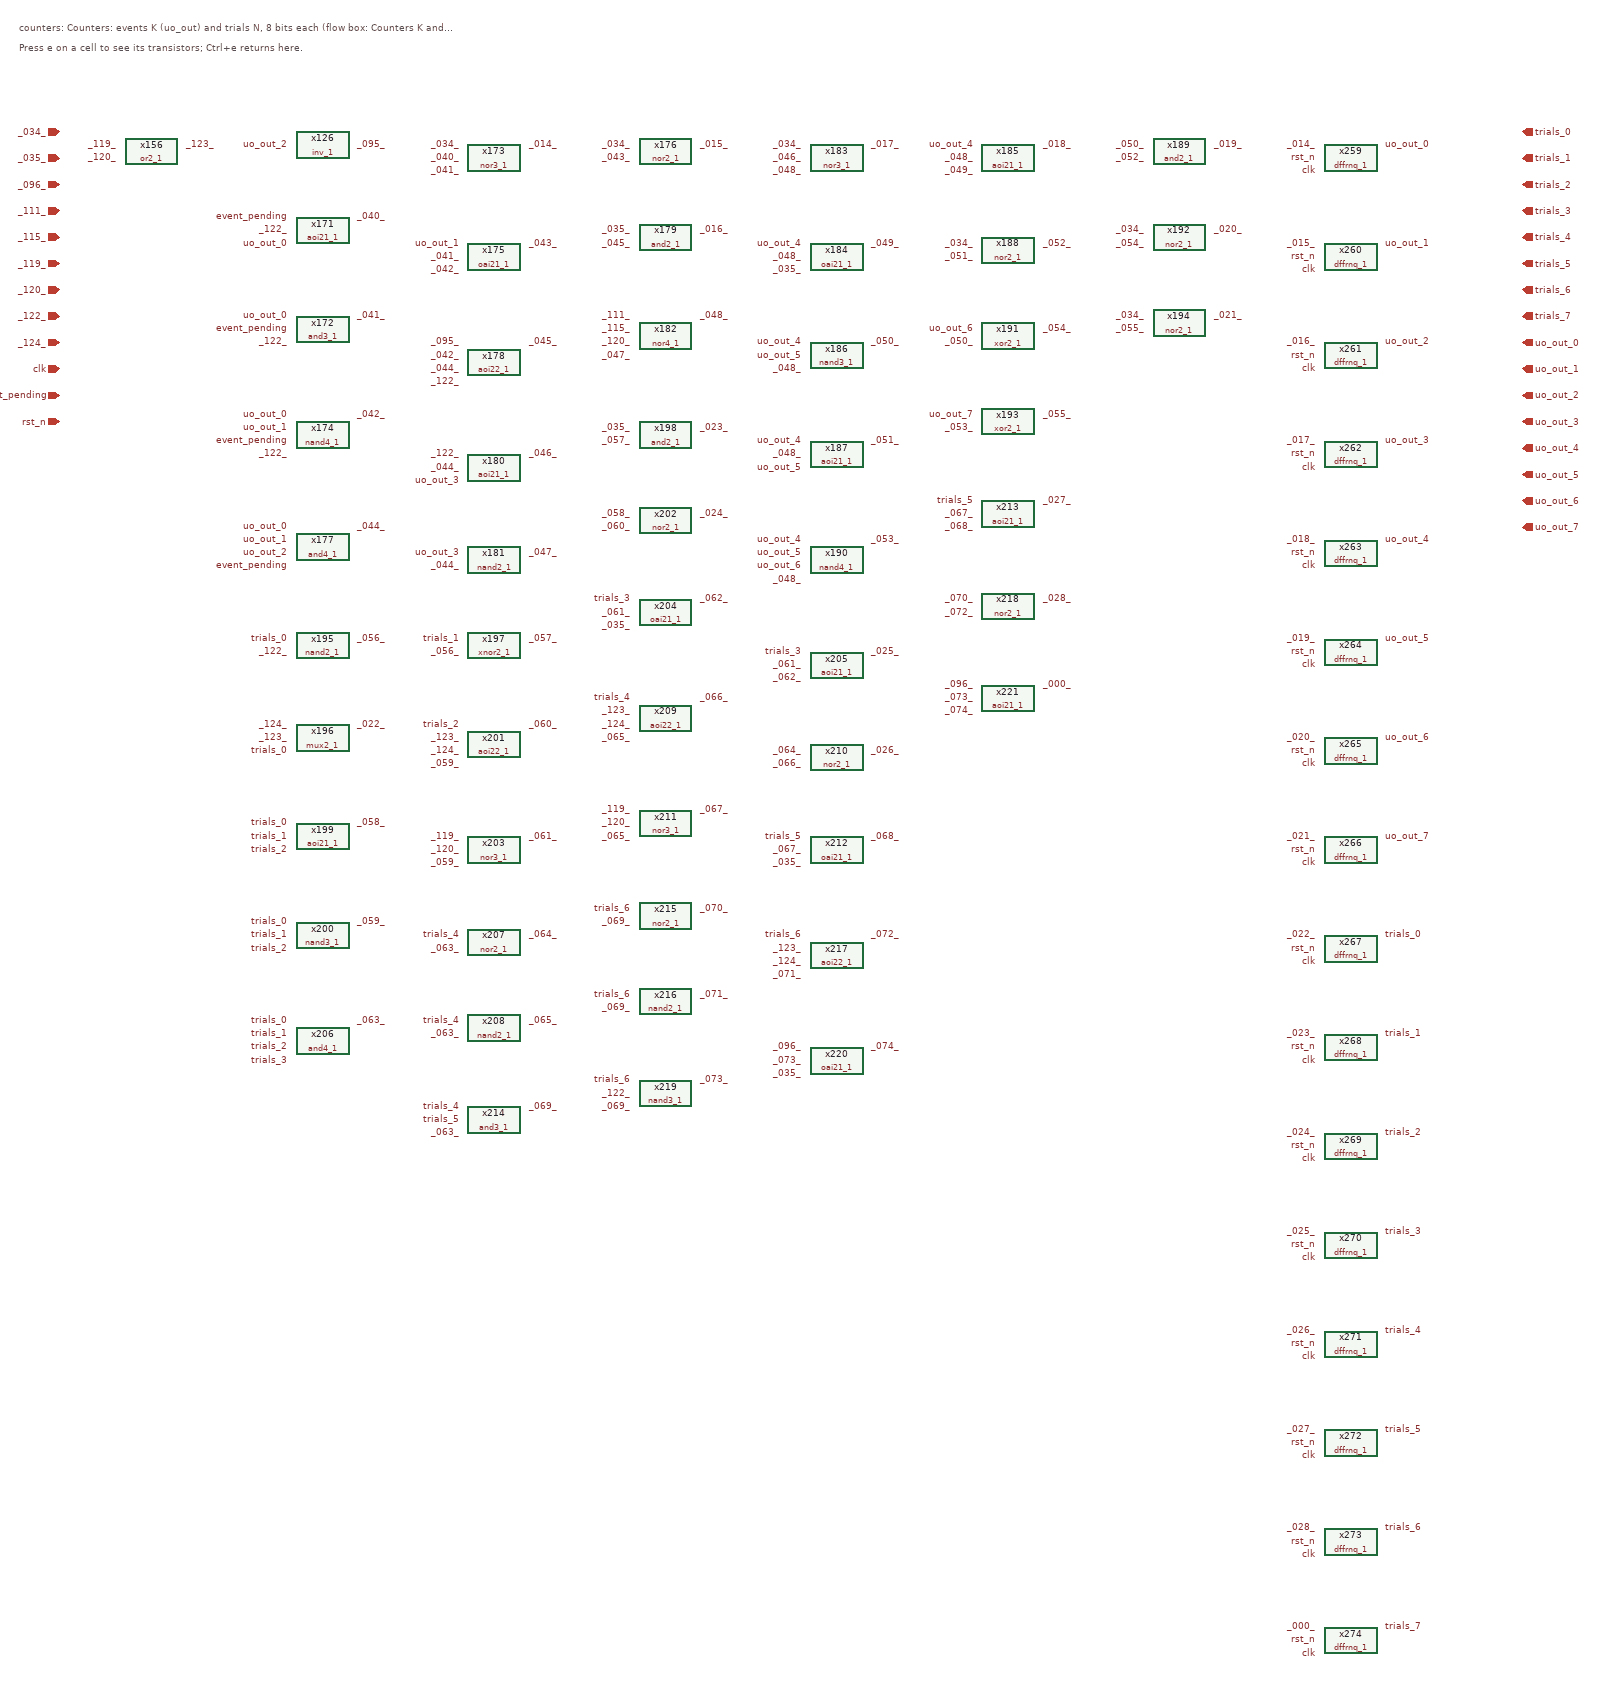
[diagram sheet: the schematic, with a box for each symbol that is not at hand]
v {xschem version=3.4.4 file_version=1.2}
G {}
K {}
V {}
S {}
E {}
T {counters: Counters: events K (uo_out) and trials N, 8 bits each   (flow box: Counters K and N)} 0 -170 0 0 0.4 0.4 {}
T {Press e on a cell to see its transistors; Ctrl+e returns here.} 0 -140 0 0 0.25 0.25 {}
C {@@ROOT@@/cells_tx/inv_1.sym} 460 20 0 0 {name=x126}
C {devices/lab_pin.sym} 410 20 0 0 {name=l1 lab=uo_out_2}
C {devices/lab_pin.sym} 510 20 0 1 {name=l2 lab=_095_}
C {@@ROOT@@/cells_tx/or2_1.sym} 200 30 0 0 {name=x156}
C {devices/lab_pin.sym} 150 20 0 0 {name=l3 lab=_119_}
C {devices/lab_pin.sym} 150 40 0 0 {name=l4 lab=_120_}
C {devices/lab_pin.sym} 250 20 0 1 {name=l5 lab=_123_}
C {@@ROOT@@/cells_tx/aoi21_1.sym} 460 150 0 0 {name=x171}
C {devices/lab_pin.sym} 410 130 0 0 {name=l6 lab=event_pending}
C {devices/lab_pin.sym} 410 150 0 0 {name=l7 lab=_122_}
C {devices/lab_pin.sym} 410 170 0 0 {name=l8 lab=uo_out_0}
C {devices/lab_pin.sym} 510 130 0 1 {name=l9 lab=_040_}
C {@@ROOT@@/cells_tx/and3_1.sym} 460 300 0 0 {name=x172}
C {devices/lab_pin.sym} 410 280 0 0 {name=l10 lab=uo_out_0}
C {devices/lab_pin.sym} 410 300 0 0 {name=l11 lab=event_pending}
C {devices/lab_pin.sym} 410 320 0 0 {name=l12 lab=_122_}
C {devices/lab_pin.sym} 510 280 0 1 {name=l13 lab=_041_}
C {@@ROOT@@/cells_tx/nor3_1.sym} 720 40 0 0 {name=x173}
C {devices/lab_pin.sym} 670 20 0 0 {name=l14 lab=_034_}
C {devices/lab_pin.sym} 670 40 0 0 {name=l15 lab=_040_}
C {devices/lab_pin.sym} 670 60 0 0 {name=l16 lab=_041_}
C {devices/lab_pin.sym} 770 20 0 1 {name=l17 lab=_014_}
C {@@ROOT@@/cells_tx/nand4_1.sym} 460 460 0 0 {name=x174}
C {devices/lab_pin.sym} 410 430 0 0 {name=l18 lab=uo_out_0}
C {devices/lab_pin.sym} 410 450 0 0 {name=l19 lab=uo_out_1}
C {devices/lab_pin.sym} 410 470 0 0 {name=l20 lab=event_pending}
C {devices/lab_pin.sym} 410 490 0 0 {name=l21 lab=_122_}
C {devices/lab_pin.sym} 510 430 0 1 {name=l22 lab=_042_}
C {@@ROOT@@/cells_tx/oai21_1.sym} 720 190 0 0 {name=x175}
C {devices/lab_pin.sym} 670 170 0 0 {name=l23 lab=uo_out_1}
C {devices/lab_pin.sym} 670 190 0 0 {name=l24 lab=_041_}
C {devices/lab_pin.sym} 670 210 0 0 {name=l25 lab=_042_}
C {devices/lab_pin.sym} 770 170 0 1 {name=l26 lab=_043_}
C {@@ROOT@@/cells_tx/nor2_1.sym} 980 30 0 0 {name=x176}
C {devices/lab_pin.sym} 930 20 0 0 {name=l27 lab=_034_}
C {devices/lab_pin.sym} 930 40 0 0 {name=l28 lab=_043_}
C {devices/lab_pin.sym} 1030 20 0 1 {name=l29 lab=_015_}
C {@@ROOT@@/cells_tx/and4_1.sym} 460 630 0 0 {name=x177}
C {devices/lab_pin.sym} 410 600 0 0 {name=l30 lab=uo_out_0}
C {devices/lab_pin.sym} 410 620 0 0 {name=l31 lab=uo_out_1}
C {devices/lab_pin.sym} 410 640 0 0 {name=l32 lab=uo_out_2}
C {devices/lab_pin.sym} 410 660 0 0 {name=l33 lab=event_pending}
C {devices/lab_pin.sym} 510 600 0 1 {name=l34 lab=_044_}
C {@@ROOT@@/cells_tx/aoi22_1.sym} 720 350 0 0 {name=x178}
C {devices/lab_pin.sym} 670 320 0 0 {name=l35 lab=_095_}
C {devices/lab_pin.sym} 670 340 0 0 {name=l36 lab=_042_}
C {devices/lab_pin.sym} 670 360 0 0 {name=l37 lab=_044_}
C {devices/lab_pin.sym} 670 380 0 0 {name=l38 lab=_122_}
C {devices/lab_pin.sym} 770 320 0 1 {name=l39 lab=_045_}
C {@@ROOT@@/cells_tx/and2_1.sym} 980 160 0 0 {name=x179}
C {devices/lab_pin.sym} 930 150 0 0 {name=l40 lab=_035_}
C {devices/lab_pin.sym} 930 170 0 0 {name=l41 lab=_045_}
C {devices/lab_pin.sym} 1030 150 0 1 {name=l42 lab=_016_}
C {@@ROOT@@/cells_tx/aoi21_1.sym} 720 510 0 0 {name=x180}
C {devices/lab_pin.sym} 670 490 0 0 {name=l43 lab=_122_}
C {devices/lab_pin.sym} 670 510 0 0 {name=l44 lab=_044_}
C {devices/lab_pin.sym} 670 530 0 0 {name=l45 lab=uo_out_3}
C {devices/lab_pin.sym} 770 490 0 1 {name=l46 lab=_046_}
C {@@ROOT@@/cells_tx/nand2_1.sym} 720 650 0 0 {name=x181}
C {devices/lab_pin.sym} 670 640 0 0 {name=l47 lab=uo_out_3}
C {devices/lab_pin.sym} 670 660 0 0 {name=l48 lab=_044_}
C {devices/lab_pin.sym} 770 640 0 1 {name=l49 lab=_047_}
C {@@ROOT@@/cells_tx/nor4_1.sym} 980 310 0 0 {name=x182}
C {devices/lab_pin.sym} 930 280 0 0 {name=l50 lab=_111_}
C {devices/lab_pin.sym} 930 300 0 0 {name=l51 lab=_115_}
C {devices/lab_pin.sym} 930 320 0 0 {name=l52 lab=_120_}
C {devices/lab_pin.sym} 930 340 0 0 {name=l53 lab=_047_}
C {devices/lab_pin.sym} 1030 280 0 1 {name=l54 lab=_048_}
C {@@ROOT@@/cells_tx/nor3_1.sym} 1240 40 0 0 {name=x183}
C {devices/lab_pin.sym} 1190 20 0 0 {name=l55 lab=_034_}
C {devices/lab_pin.sym} 1190 40 0 0 {name=l56 lab=_046_}
C {devices/lab_pin.sym} 1190 60 0 0 {name=l57 lab=_048_}
C {devices/lab_pin.sym} 1290 20 0 1 {name=l58 lab=_017_}
C {@@ROOT@@/cells_tx/oai21_1.sym} 1240 190 0 0 {name=x184}
C {devices/lab_pin.sym} 1190 170 0 0 {name=l59 lab=uo_out_4}
C {devices/lab_pin.sym} 1190 190 0 0 {name=l60 lab=_048_}
C {devices/lab_pin.sym} 1190 210 0 0 {name=l61 lab=_035_}
C {devices/lab_pin.sym} 1290 170 0 1 {name=l62 lab=_049_}
C {@@ROOT@@/cells_tx/aoi21_1.sym} 1500 40 0 0 {name=x185}
C {devices/lab_pin.sym} 1450 20 0 0 {name=l63 lab=uo_out_4}
C {devices/lab_pin.sym} 1450 40 0 0 {name=l64 lab=_048_}
C {devices/lab_pin.sym} 1450 60 0 0 {name=l65 lab=_049_}
C {devices/lab_pin.sym} 1550 20 0 1 {name=l66 lab=_018_}
C {@@ROOT@@/cells_tx/nand3_1.sym} 1240 340 0 0 {name=x186}
C {devices/lab_pin.sym} 1190 320 0 0 {name=l67 lab=uo_out_4}
C {devices/lab_pin.sym} 1190 340 0 0 {name=l68 lab=uo_out_5}
C {devices/lab_pin.sym} 1190 360 0 0 {name=l69 lab=_048_}
C {devices/lab_pin.sym} 1290 320 0 1 {name=l70 lab=_050_}
C {@@ROOT@@/cells_tx/aoi21_1.sym} 1240 490 0 0 {name=x187}
C {devices/lab_pin.sym} 1190 470 0 0 {name=l71 lab=uo_out_4}
C {devices/lab_pin.sym} 1190 490 0 0 {name=l72 lab=_048_}
C {devices/lab_pin.sym} 1190 510 0 0 {name=l73 lab=uo_out_5}
C {devices/lab_pin.sym} 1290 470 0 1 {name=l74 lab=_051_}
C {@@ROOT@@/cells_tx/nor2_1.sym} 1500 180 0 0 {name=x188}
C {devices/lab_pin.sym} 1450 170 0 0 {name=l75 lab=_034_}
C {devices/lab_pin.sym} 1450 190 0 0 {name=l76 lab=_051_}
C {devices/lab_pin.sym} 1550 170 0 1 {name=l77 lab=_052_}
C {@@ROOT@@/cells_tx/and2_1.sym} 1760 30 0 0 {name=x189}
C {devices/lab_pin.sym} 1710 20 0 0 {name=l78 lab=_050_}
C {devices/lab_pin.sym} 1710 40 0 0 {name=l79 lab=_052_}
C {devices/lab_pin.sym} 1810 20 0 1 {name=l80 lab=_019_}
C {@@ROOT@@/cells_tx/nand4_1.sym} 1240 650 0 0 {name=x190}
C {devices/lab_pin.sym} 1190 620 0 0 {name=l81 lab=uo_out_4}
C {devices/lab_pin.sym} 1190 640 0 0 {name=l82 lab=uo_out_5}
C {devices/lab_pin.sym} 1190 660 0 0 {name=l83 lab=uo_out_6}
C {devices/lab_pin.sym} 1190 680 0 0 {name=l84 lab=_048_}
C {devices/lab_pin.sym} 1290 620 0 1 {name=l85 lab=_053_}
C {@@ROOT@@/cells_tx/xor2_1.sym} 1500 310 0 0 {name=x191}
C {devices/lab_pin.sym} 1450 300 0 0 {name=l86 lab=uo_out_6}
C {devices/lab_pin.sym} 1450 320 0 0 {name=l87 lab=_050_}
C {devices/lab_pin.sym} 1550 300 0 1 {name=l88 lab=_054_}
C {@@ROOT@@/cells_tx/nor2_1.sym} 1760 160 0 0 {name=x192}
C {devices/lab_pin.sym} 1710 150 0 0 {name=l89 lab=_034_}
C {devices/lab_pin.sym} 1710 170 0 0 {name=l90 lab=_054_}
C {devices/lab_pin.sym} 1810 150 0 1 {name=l91 lab=_020_}
C {@@ROOT@@/cells_tx/xor2_1.sym} 1500 440 0 0 {name=x193}
C {devices/lab_pin.sym} 1450 430 0 0 {name=l92 lab=uo_out_7}
C {devices/lab_pin.sym} 1450 450 0 0 {name=l93 lab=_053_}
C {devices/lab_pin.sym} 1550 430 0 1 {name=l94 lab=_055_}
C {@@ROOT@@/cells_tx/nor2_1.sym} 1760 290 0 0 {name=x194}
C {devices/lab_pin.sym} 1710 280 0 0 {name=l95 lab=_034_}
C {devices/lab_pin.sym} 1710 300 0 0 {name=l96 lab=_055_}
C {devices/lab_pin.sym} 1810 280 0 1 {name=l97 lab=_021_}
C {@@ROOT@@/cells_tx/nand2_1.sym} 460 780 0 0 {name=x195}
C {devices/lab_pin.sym} 410 770 0 0 {name=l98 lab=trials_0}
C {devices/lab_pin.sym} 410 790 0 0 {name=l99 lab=_122_}
C {devices/lab_pin.sym} 510 770 0 1 {name=l100 lab=_056_}
C {@@ROOT@@/cells_tx/mux2_1.sym} 460 920 0 0 {name=x196}
C {devices/lab_pin.sym} 410 900 0 0 {name=l101 lab=_124_}
C {devices/lab_pin.sym} 410 920 0 0 {name=l102 lab=_123_}
C {devices/lab_pin.sym} 410 940 0 0 {name=l103 lab=trials_0}
C {devices/lab_pin.sym} 510 900 0 1 {name=l104 lab=_022_}
C {@@ROOT@@/cells_tx/xnor2_1.sym} 720 780 0 0 {name=x197}
C {devices/lab_pin.sym} 670 770 0 0 {name=l105 lab=trials_1}
C {devices/lab_pin.sym} 670 790 0 0 {name=l106 lab=_056_}
C {devices/lab_pin.sym} 770 770 0 1 {name=l107 lab=_057_}
C {@@ROOT@@/cells_tx/and2_1.sym} 980 460 0 0 {name=x198}
C {devices/lab_pin.sym} 930 450 0 0 {name=l108 lab=_035_}
C {devices/lab_pin.sym} 930 470 0 0 {name=l109 lab=_057_}
C {devices/lab_pin.sym} 1030 450 0 1 {name=l110 lab=_023_}
C {@@ROOT@@/cells_tx/aoi21_1.sym} 460 1070 0 0 {name=x199}
C {devices/lab_pin.sym} 410 1050 0 0 {name=l111 lab=trials_0}
C {devices/lab_pin.sym} 410 1070 0 0 {name=l112 lab=trials_1}
C {devices/lab_pin.sym} 410 1090 0 0 {name=l113 lab=trials_2}
C {devices/lab_pin.sym} 510 1050 0 1 {name=l114 lab=_058_}
C {@@ROOT@@/cells_tx/nand3_1.sym} 460 1220 0 0 {name=x200}
C {devices/lab_pin.sym} 410 1200 0 0 {name=l115 lab=trials_0}
C {devices/lab_pin.sym} 410 1220 0 0 {name=l116 lab=trials_1}
C {devices/lab_pin.sym} 410 1240 0 0 {name=l117 lab=trials_2}
C {devices/lab_pin.sym} 510 1200 0 1 {name=l118 lab=_059_}
C {@@ROOT@@/cells_tx/aoi22_1.sym} 720 930 0 0 {name=x201}
C {devices/lab_pin.sym} 670 900 0 0 {name=l119 lab=trials_2}
C {devices/lab_pin.sym} 670 920 0 0 {name=l120 lab=_123_}
C {devices/lab_pin.sym} 670 940 0 0 {name=l121 lab=_124_}
C {devices/lab_pin.sym} 670 960 0 0 {name=l122 lab=_059_}
C {devices/lab_pin.sym} 770 900 0 1 {name=l123 lab=_060_}
C {@@ROOT@@/cells_tx/nor2_1.sym} 980 590 0 0 {name=x202}
C {devices/lab_pin.sym} 930 580 0 0 {name=l124 lab=_058_}
C {devices/lab_pin.sym} 930 600 0 0 {name=l125 lab=_060_}
C {devices/lab_pin.sym} 1030 580 0 1 {name=l126 lab=_024_}
C {@@ROOT@@/cells_tx/nor3_1.sym} 720 1090 0 0 {name=x203}
C {devices/lab_pin.sym} 670 1070 0 0 {name=l127 lab=_119_}
C {devices/lab_pin.sym} 670 1090 0 0 {name=l128 lab=_120_}
C {devices/lab_pin.sym} 670 1110 0 0 {name=l129 lab=_059_}
C {devices/lab_pin.sym} 770 1070 0 1 {name=l130 lab=_061_}
C {@@ROOT@@/cells_tx/oai21_1.sym} 980 730 0 0 {name=x204}
C {devices/lab_pin.sym} 930 710 0 0 {name=l131 lab=trials_3}
C {devices/lab_pin.sym} 930 730 0 0 {name=l132 lab=_061_}
C {devices/lab_pin.sym} 930 750 0 0 {name=l133 lab=_035_}
C {devices/lab_pin.sym} 1030 710 0 1 {name=l134 lab=_062_}
C {@@ROOT@@/cells_tx/aoi21_1.sym} 1240 810 0 0 {name=x205}
C {devices/lab_pin.sym} 1190 790 0 0 {name=l135 lab=trials_3}
C {devices/lab_pin.sym} 1190 810 0 0 {name=l136 lab=_061_}
C {devices/lab_pin.sym} 1190 830 0 0 {name=l137 lab=_062_}
C {devices/lab_pin.sym} 1290 790 0 1 {name=l138 lab=_025_}
C {@@ROOT@@/cells_tx/and4_1.sym} 460 1380 0 0 {name=x206}
C {devices/lab_pin.sym} 410 1350 0 0 {name=l139 lab=trials_0}
C {devices/lab_pin.sym} 410 1370 0 0 {name=l140 lab=trials_1}
C {devices/lab_pin.sym} 410 1390 0 0 {name=l141 lab=trials_2}
C {devices/lab_pin.sym} 410 1410 0 0 {name=l142 lab=trials_3}
C {devices/lab_pin.sym} 510 1350 0 1 {name=l143 lab=_063_}
C {@@ROOT@@/cells_tx/nor2_1.sym} 720 1230 0 0 {name=x207}
C {devices/lab_pin.sym} 670 1220 0 0 {name=l144 lab=trials_4}
C {devices/lab_pin.sym} 670 1240 0 0 {name=l145 lab=_063_}
C {devices/lab_pin.sym} 770 1220 0 1 {name=l146 lab=_064_}
C {@@ROOT@@/cells_tx/nand2_1.sym} 720 1360 0 0 {name=x208}
C {devices/lab_pin.sym} 670 1350 0 0 {name=l147 lab=trials_4}
C {devices/lab_pin.sym} 670 1370 0 0 {name=l148 lab=_063_}
C {devices/lab_pin.sym} 770 1350 0 1 {name=l149 lab=_065_}
C {@@ROOT@@/cells_tx/aoi22_1.sym} 980 890 0 0 {name=x209}
C {devices/lab_pin.sym} 930 860 0 0 {name=l150 lab=trials_4}
C {devices/lab_pin.sym} 930 880 0 0 {name=l151 lab=_123_}
C {devices/lab_pin.sym} 930 900 0 0 {name=l152 lab=_124_}
C {devices/lab_pin.sym} 930 920 0 0 {name=l153 lab=_065_}
C {devices/lab_pin.sym} 1030 860 0 1 {name=l154 lab=_066_}
C {@@ROOT@@/cells_tx/nor2_1.sym} 1240 950 0 0 {name=x210}
C {devices/lab_pin.sym} 1190 940 0 0 {name=l155 lab=_064_}
C {devices/lab_pin.sym} 1190 960 0 0 {name=l156 lab=_066_}
C {devices/lab_pin.sym} 1290 940 0 1 {name=l157 lab=_026_}
C {@@ROOT@@/cells_tx/nor3_1.sym} 980 1050 0 0 {name=x211}
C {devices/lab_pin.sym} 930 1030 0 0 {name=l158 lab=_119_}
C {devices/lab_pin.sym} 930 1050 0 0 {name=l159 lab=_120_}
C {devices/lab_pin.sym} 930 1070 0 0 {name=l160 lab=_065_}
C {devices/lab_pin.sym} 1030 1030 0 1 {name=l161 lab=_067_}
C {@@ROOT@@/cells_tx/oai21_1.sym} 1240 1090 0 0 {name=x212}
C {devices/lab_pin.sym} 1190 1070 0 0 {name=l162 lab=trials_5}
C {devices/lab_pin.sym} 1190 1090 0 0 {name=l163 lab=_067_}
C {devices/lab_pin.sym} 1190 1110 0 0 {name=l164 lab=_035_}
C {devices/lab_pin.sym} 1290 1070 0 1 {name=l165 lab=_068_}
C {@@ROOT@@/cells_tx/aoi21_1.sym} 1500 580 0 0 {name=x213}
C {devices/lab_pin.sym} 1450 560 0 0 {name=l166 lab=trials_5}
C {devices/lab_pin.sym} 1450 580 0 0 {name=l167 lab=_067_}
C {devices/lab_pin.sym} 1450 600 0 0 {name=l168 lab=_068_}
C {devices/lab_pin.sym} 1550 560 0 1 {name=l169 lab=_027_}
C {@@ROOT@@/cells_tx/and3_1.sym} 720 1500 0 0 {name=x214}
C {devices/lab_pin.sym} 670 1480 0 0 {name=l170 lab=trials_4}
C {devices/lab_pin.sym} 670 1500 0 0 {name=l171 lab=trials_5}
C {devices/lab_pin.sym} 670 1520 0 0 {name=l172 lab=_063_}
C {devices/lab_pin.sym} 770 1480 0 1 {name=l173 lab=_069_}
C {@@ROOT@@/cells_tx/nor2_1.sym} 980 1190 0 0 {name=x215}
C {devices/lab_pin.sym} 930 1180 0 0 {name=l174 lab=trials_6}
C {devices/lab_pin.sym} 930 1200 0 0 {name=l175 lab=_069_}
C {devices/lab_pin.sym} 1030 1180 0 1 {name=l176 lab=_070_}
C {@@ROOT@@/cells_tx/nand2_1.sym} 980 1320 0 0 {name=x216}
C {devices/lab_pin.sym} 930 1310 0 0 {name=l177 lab=trials_6}
C {devices/lab_pin.sym} 930 1330 0 0 {name=l178 lab=_069_}
C {devices/lab_pin.sym} 1030 1310 0 1 {name=l179 lab=_071_}
C {@@ROOT@@/cells_tx/aoi22_1.sym} 1240 1250 0 0 {name=x217}
C {devices/lab_pin.sym} 1190 1220 0 0 {name=l180 lab=trials_6}
C {devices/lab_pin.sym} 1190 1240 0 0 {name=l181 lab=_123_}
C {devices/lab_pin.sym} 1190 1260 0 0 {name=l182 lab=_124_}
C {devices/lab_pin.sym} 1190 1280 0 0 {name=l183 lab=_071_}
C {devices/lab_pin.sym} 1290 1220 0 1 {name=l184 lab=_072_}
C {@@ROOT@@/cells_tx/nor2_1.sym} 1500 720 0 0 {name=x218}
C {devices/lab_pin.sym} 1450 710 0 0 {name=l185 lab=_070_}
C {devices/lab_pin.sym} 1450 730 0 0 {name=l186 lab=_072_}
C {devices/lab_pin.sym} 1550 710 0 1 {name=l187 lab=_028_}
C {@@ROOT@@/cells_tx/nand3_1.sym} 980 1460 0 0 {name=x219}
C {devices/lab_pin.sym} 930 1440 0 0 {name=l188 lab=trials_6}
C {devices/lab_pin.sym} 930 1460 0 0 {name=l189 lab=_122_}
C {devices/lab_pin.sym} 930 1480 0 0 {name=l190 lab=_069_}
C {devices/lab_pin.sym} 1030 1440 0 1 {name=l191 lab=_073_}
C {@@ROOT@@/cells_tx/oai21_1.sym} 1240 1410 0 0 {name=x220}
C {devices/lab_pin.sym} 1190 1390 0 0 {name=l192 lab=_096_}
C {devices/lab_pin.sym} 1190 1410 0 0 {name=l193 lab=_073_}
C {devices/lab_pin.sym} 1190 1430 0 0 {name=l194 lab=_035_}
C {devices/lab_pin.sym} 1290 1390 0 1 {name=l195 lab=_074_}
C {@@ROOT@@/cells_tx/aoi21_1.sym} 1500 860 0 0 {name=x221}
C {devices/lab_pin.sym} 1450 840 0 0 {name=l196 lab=_096_}
C {devices/lab_pin.sym} 1450 860 0 0 {name=l197 lab=_073_}
C {devices/lab_pin.sym} 1450 880 0 0 {name=l198 lab=_074_}
C {devices/lab_pin.sym} 1550 840 0 1 {name=l199 lab=_000_}
C {@@ROOT@@/cells_tx/dffrnq_1.sym} 2020 40 0 0 {name=x259}
C {devices/lab_pin.sym} 1970 20 0 0 {name=l200 lab=_014_}
C {devices/lab_pin.sym} 1970 40 0 0 {name=l201 lab=rst_n}
C {devices/lab_pin.sym} 1970 60 0 0 {name=l202 lab=clk}
C {devices/lab_pin.sym} 2070 20 0 1 {name=l203 lab=uo_out_0}
C {@@ROOT@@/cells_tx/dffrnq_1.sym} 2020 190 0 0 {name=x260}
C {devices/lab_pin.sym} 1970 170 0 0 {name=l204 lab=_015_}
C {devices/lab_pin.sym} 1970 190 0 0 {name=l205 lab=rst_n}
C {devices/lab_pin.sym} 1970 210 0 0 {name=l206 lab=clk}
C {devices/lab_pin.sym} 2070 170 0 1 {name=l207 lab=uo_out_1}
C {@@ROOT@@/cells_tx/dffrnq_1.sym} 2020 340 0 0 {name=x261}
C {devices/lab_pin.sym} 1970 320 0 0 {name=l208 lab=_016_}
C {devices/lab_pin.sym} 1970 340 0 0 {name=l209 lab=rst_n}
C {devices/lab_pin.sym} 1970 360 0 0 {name=l210 lab=clk}
C {devices/lab_pin.sym} 2070 320 0 1 {name=l211 lab=uo_out_2}
C {@@ROOT@@/cells_tx/dffrnq_1.sym} 2020 490 0 0 {name=x262}
C {devices/lab_pin.sym} 1970 470 0 0 {name=l212 lab=_017_}
C {devices/lab_pin.sym} 1970 490 0 0 {name=l213 lab=rst_n}
C {devices/lab_pin.sym} 1970 510 0 0 {name=l214 lab=clk}
C {devices/lab_pin.sym} 2070 470 0 1 {name=l215 lab=uo_out_3}
C {@@ROOT@@/cells_tx/dffrnq_1.sym} 2020 640 0 0 {name=x263}
C {devices/lab_pin.sym} 1970 620 0 0 {name=l216 lab=_018_}
C {devices/lab_pin.sym} 1970 640 0 0 {name=l217 lab=rst_n}
C {devices/lab_pin.sym} 1970 660 0 0 {name=l218 lab=clk}
C {devices/lab_pin.sym} 2070 620 0 1 {name=l219 lab=uo_out_4}
C {@@ROOT@@/cells_tx/dffrnq_1.sym} 2020 790 0 0 {name=x264}
C {devices/lab_pin.sym} 1970 770 0 0 {name=l220 lab=_019_}
C {devices/lab_pin.sym} 1970 790 0 0 {name=l221 lab=rst_n}
C {devices/lab_pin.sym} 1970 810 0 0 {name=l222 lab=clk}
C {devices/lab_pin.sym} 2070 770 0 1 {name=l223 lab=uo_out_5}
C {@@ROOT@@/cells_tx/dffrnq_1.sym} 2020 940 0 0 {name=x265}
C {devices/lab_pin.sym} 1970 920 0 0 {name=l224 lab=_020_}
C {devices/lab_pin.sym} 1970 940 0 0 {name=l225 lab=rst_n}
C {devices/lab_pin.sym} 1970 960 0 0 {name=l226 lab=clk}
C {devices/lab_pin.sym} 2070 920 0 1 {name=l227 lab=uo_out_6}
C {@@ROOT@@/cells_tx/dffrnq_1.sym} 2020 1090 0 0 {name=x266}
C {devices/lab_pin.sym} 1970 1070 0 0 {name=l228 lab=_021_}
C {devices/lab_pin.sym} 1970 1090 0 0 {name=l229 lab=rst_n}
C {devices/lab_pin.sym} 1970 1110 0 0 {name=l230 lab=clk}
C {devices/lab_pin.sym} 2070 1070 0 1 {name=l231 lab=uo_out_7}
C {@@ROOT@@/cells_tx/dffrnq_1.sym} 2020 1240 0 0 {name=x267}
C {devices/lab_pin.sym} 1970 1220 0 0 {name=l232 lab=_022_}
C {devices/lab_pin.sym} 1970 1240 0 0 {name=l233 lab=rst_n}
C {devices/lab_pin.sym} 1970 1260 0 0 {name=l234 lab=clk}
C {devices/lab_pin.sym} 2070 1220 0 1 {name=l235 lab=trials_0}
C {@@ROOT@@/cells_tx/dffrnq_1.sym} 2020 1390 0 0 {name=x268}
C {devices/lab_pin.sym} 1970 1370 0 0 {name=l236 lab=_023_}
C {devices/lab_pin.sym} 1970 1390 0 0 {name=l237 lab=rst_n}
C {devices/lab_pin.sym} 1970 1410 0 0 {name=l238 lab=clk}
C {devices/lab_pin.sym} 2070 1370 0 1 {name=l239 lab=trials_1}
C {@@ROOT@@/cells_tx/dffrnq_1.sym} 2020 1540 0 0 {name=x269}
C {devices/lab_pin.sym} 1970 1520 0 0 {name=l240 lab=_024_}
C {devices/lab_pin.sym} 1970 1540 0 0 {name=l241 lab=rst_n}
C {devices/lab_pin.sym} 1970 1560 0 0 {name=l242 lab=clk}
C {devices/lab_pin.sym} 2070 1520 0 1 {name=l243 lab=trials_2}
C {@@ROOT@@/cells_tx/dffrnq_1.sym} 2020 1690 0 0 {name=x270}
C {devices/lab_pin.sym} 1970 1670 0 0 {name=l244 lab=_025_}
C {devices/lab_pin.sym} 1970 1690 0 0 {name=l245 lab=rst_n}
C {devices/lab_pin.sym} 1970 1710 0 0 {name=l246 lab=clk}
C {devices/lab_pin.sym} 2070 1670 0 1 {name=l247 lab=trials_3}
C {@@ROOT@@/cells_tx/dffrnq_1.sym} 2020 1840 0 0 {name=x271}
C {devices/lab_pin.sym} 1970 1820 0 0 {name=l248 lab=_026_}
C {devices/lab_pin.sym} 1970 1840 0 0 {name=l249 lab=rst_n}
C {devices/lab_pin.sym} 1970 1860 0 0 {name=l250 lab=clk}
C {devices/lab_pin.sym} 2070 1820 0 1 {name=l251 lab=trials_4}
C {@@ROOT@@/cells_tx/dffrnq_1.sym} 2020 1990 0 0 {name=x272}
C {devices/lab_pin.sym} 1970 1970 0 0 {name=l252 lab=_027_}
C {devices/lab_pin.sym} 1970 1990 0 0 {name=l253 lab=rst_n}
C {devices/lab_pin.sym} 1970 2010 0 0 {name=l254 lab=clk}
C {devices/lab_pin.sym} 2070 1970 0 1 {name=l255 lab=trials_5}
C {@@ROOT@@/cells_tx/dffrnq_1.sym} 2020 2140 0 0 {name=x273}
C {devices/lab_pin.sym} 1970 2120 0 0 {name=l256 lab=_028_}
C {devices/lab_pin.sym} 1970 2140 0 0 {name=l257 lab=rst_n}
C {devices/lab_pin.sym} 1970 2160 0 0 {name=l258 lab=clk}
C {devices/lab_pin.sym} 2070 2120 0 1 {name=l259 lab=trials_6}
C {@@ROOT@@/cells_tx/dffrnq_1.sym} 2020 2290 0 0 {name=x274}
C {devices/lab_pin.sym} 1970 2270 0 0 {name=l260 lab=_000_}
C {devices/lab_pin.sym} 1970 2290 0 0 {name=l261 lab=rst_n}
C {devices/lab_pin.sym} 1970 2310 0 0 {name=l262 lab=clk}
C {devices/lab_pin.sym} 2070 2270 0 1 {name=l263 lab=trials_7}
C {devices/ipin.sym} 60 0 0 0 {name=p264 lab=_034_}
C {devices/ipin.sym} 60 40 0 0 {name=p265 lab=_035_}
C {devices/ipin.sym} 60 80 0 0 {name=p266 lab=_096_}
C {devices/ipin.sym} 60 120 0 0 {name=p267 lab=_111_}
C {devices/ipin.sym} 60 160 0 0 {name=p268 lab=_115_}
C {devices/ipin.sym} 60 200 0 0 {name=p269 lab=_119_}
C {devices/ipin.sym} 60 240 0 0 {name=p270 lab=_120_}
C {devices/ipin.sym} 60 280 0 0 {name=p271 lab=_122_}
C {devices/ipin.sym} 60 320 0 0 {name=p272 lab=_124_}
C {devices/ipin.sym} 60 360 0 0 {name=p273 lab=clk}
C {devices/ipin.sym} 60 400 0 0 {name=p274 lab=event_pending}
C {devices/ipin.sym} 60 440 0 0 {name=p275 lab=rst_n}
C {devices/opin.sym} 2280 0 0 0 {name=p276 lab=trials_0}
C {devices/opin.sym} 2280 40 0 0 {name=p277 lab=trials_1}
C {devices/opin.sym} 2280 80 0 0 {name=p278 lab=trials_2}
C {devices/opin.sym} 2280 120 0 0 {name=p279 lab=trials_3}
C {devices/opin.sym} 2280 160 0 0 {name=p280 lab=trials_4}
C {devices/opin.sym} 2280 200 0 0 {name=p281 lab=trials_5}
C {devices/opin.sym} 2280 240 0 0 {name=p282 lab=trials_6}
C {devices/opin.sym} 2280 280 0 0 {name=p283 lab=trials_7}
C {devices/opin.sym} 2280 320 0 0 {name=p284 lab=uo_out_0}
C {devices/opin.sym} 2280 360 0 0 {name=p285 lab=uo_out_1}
C {devices/opin.sym} 2280 400 0 0 {name=p286 lab=uo_out_2}
C {devices/opin.sym} 2280 440 0 0 {name=p287 lab=uo_out_3}
C {devices/opin.sym} 2280 480 0 0 {name=p288 lab=uo_out_4}
C {devices/opin.sym} 2280 520 0 0 {name=p289 lab=uo_out_5}
C {devices/opin.sym} 2280 560 0 0 {name=p290 lab=uo_out_6}
C {devices/opin.sym} 2280 600 0 0 {name=p291 lab=uo_out_7}
